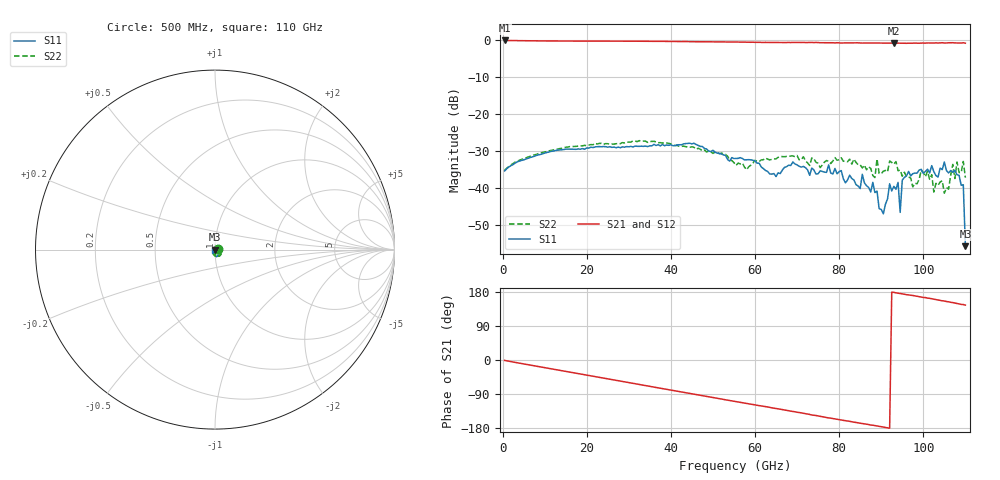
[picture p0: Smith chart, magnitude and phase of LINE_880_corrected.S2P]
!  2-Port S-parameters saved by WinCal
! VAR MeasName=S-Parameters (RAW_DATA) read from VNA (XF)
! VAR MeasDate=30.04.2014 13:13:18
! VAR NAME=LINE_880_corrected
! VAR FILENAME=LINE_880_corrected.S2P
! VAR DATE=30.04.2014 13:13:18
! VAR PHYS_PORTS=1,2
! VAR ObjTypeName=DATASET
! VAR IndexType=Frequency
# Hz S RI R 50
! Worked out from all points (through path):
!   220 points, 500 MHz to 110 GHz, reference 50 ohm
!   highest |S21| = -0.16 dB at 500 MHz (marker M1); lowest = -1.0 dB at 93 GHz (marker M2)
!   group delay of S21, straight-line fit = 5.4 ps
!   lowest |S11| = -55.6 dB at 110 GHz (marker M3), VSWR 1.00, Z = 50.2 - j0.067 ohm
!   |S11| at or under -10 dB: start of sweep to end of sweep
!   |S22| runs from -41.3 to -27.1 dB; largest |S21 - S12| = 0.02
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5e8  0.017 0.00208  0.9819 -0.0192  0.9819 -0.0208  0.0175 0.00247
1.9e10  0.0329 -0.00969  0.7614 -0.5891  0.7614 -0.5894  0.0362 -0.00972
3.7e10  0.0218 -0.032  0.2717 -0.9174  0.2704 -0.918  0.0193 -0.0364
5.55e10  0.000263 -0.0253  -0.317 -0.8816  -0.324 -0.8784  -0.00743 -0.019
6.5e10  -0.0032 -0.014  -0.5684 -0.7274  -0.5671 -0.7311  -0.00472 -0.0244
7.35e10  -0.00577 -0.0179  -0.7583 -0.5275  -0.7459 -0.5427  -0.000402 -0.0257
8.5e10  -0.00846 -0.00523  -0.8834 -0.2076  -0.8833 -0.2264  -0.00877 -0.0188
8.55e10  -0.0129 -0.00857  -0.8849 -0.1938  -0.8823 -0.2057  -0.0087 -0.0167
9.05e10  -0.00255 0.00376  -0.9034 -0.0472  -0.901 -0.0515  0.000599 -0.017
9.2e10  -0.00965 0.00629  -0.9015 -0.000387  -0.9013 -0.00829  -0.01 -0.0211
9.3e10  -0.00584 0.00891  -0.8949 0.024  -0.8995 0.0213  -0.00702 -0.02
9.4e10  0.00314 0.0116  -0.9021 0.0565  -0.899 0.0521  -0.0027 -0.0171
9.45e10  0.00084 0.00467  -0.8999 0.0662  -0.898 0.0666  -0.00538 -0.0168
9.5e10  0.00637 0.0112  -0.8982 0.086  -0.8962 0.0824  -0.00166 -0.0145
9.65e10  0.0121 0.0117  -0.8933 0.1303  -0.894 0.1191  0.00364 -0.0137
1.01e11  0.018 -0.0017  -0.8713 0.2603  -0.8755 0.2547  0.00174 -0.0169
1.025e11  0.0161 -0.00465  -0.8554 0.303  -0.8589 0.2955  0.00196 -0.0087
1.05e11  0.0208 -0.00882  -0.827 0.3754  -0.8326 0.3698  0.00812 0.00286
1.07e11  0.0147 -0.00739  -0.8051 0.4361  -0.8051 0.4361  0.0207 -0.00337
1.075e11  0.0157 -0.0078  -0.791 0.4504  -0.7893 0.444  0.0129 -0.00426
1.095e11  0.00931 -0.00618  -0.76 0.5075  -0.7639 0.4981  0.0223 -0.00581
1.1e11  0.00152 -0.000668  -0.7391 0.5183  -0.7481 0.5059  0.0133 -0.00415
